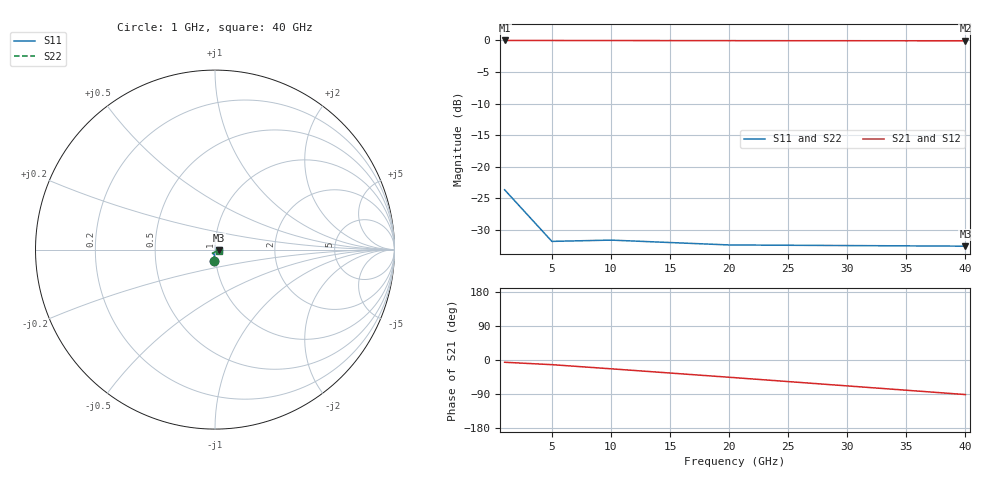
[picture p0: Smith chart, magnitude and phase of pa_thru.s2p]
! Generated by circuitRF - EM: Palace
! circuitRF-EM setup: g_thru_sheets
! circuitRF-EM layout: thru/layout/thru.clay
! circuitRF-EM written: 2026-11-04 16:05:03Z
! circuitRF-EM geometry: f9fb279984360a3e
! circuitRF-EM mesh: be36879526fbbc1a
! circuitRF-EM ports: e0915e1a10e1aaad
! circuitRF-EM model: Palace 0.18.1 (0dc74cd, schema 1-7-0)
! Port[1] = port/1
! Port[2] = port/2
! circuitRF-EM port 1: 'port/1' from 'airbox/zmin' to 'Metal1/1', wave (mode 1), 50 Ohm: Palace's S is referred to the mode's own impedance Z_PV, renormalised here to 50 Ohm; reference plane 0 um into the structure from the port face
! circuitRF-EM port 2: 'port/2' from 'airbox/zmin' to 'Metal1/1', wave (mode 1), 50 Ohm: Palace's S is referred to the mode's own impedance Z_PV, renormalised here to 50 Ohm; reference plane 0 um into the structure from the port face
! circuitRF-EM 3D mesh: 13,400 elements initially, 13,400 finally, 0 adaptive pass(es), element order 2
! circuitRF-EM 3D operating temperature: 20 C
! circuitRF-EM 3D run: preset Standard; 13400 -> 13400 tetrahedra; 93238 unknowns; 0 refinement pass(es); 5 frequency sample(s)
! circuitRF-EM 3D run cost: wall 244 s; Palace peak memory 1.4 GB
! circuitRF-EM 3D DC row: circuitRF conduction solve of the conductors, 368 elements, 0.2 s; ports as terminal pairs
! circuitRF-EM: re-running the EM setup rewrites this file. If circuitRF reports it as stale, the layout's cross-section changed after this file was written.
# GHz S RI R 50
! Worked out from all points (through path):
!   5 points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, 1 GHz to 40 GHz, reference 50 ohm
!   highest |S21| = -0.01 dB at 1 GHz (marker M1); lowest = -0.1 dB at 40 GHz (marker M2)
!   lowest |S11| = -32.6 dB at 40 GHz (marker M3), VSWR 1.05, Z = 52.4 - j0.482 ohm
!   |S11| at or under -10 dB: start of sweep to end of sweep
!   |S22| runs from -32.6 to -23.6 dB; largest |S21 - S12| = 3.6e-06
1  -0.00359 -0.0657  0.9932 -0.1039  0.9932 -0.1039  -0.00359 -0.0657
5  -0.00353 -0.0254  0.975 -0.2127  0.975 -0.2127  -0.00352 -0.0254
10  -0.00783 -0.0251  0.916 -0.3931  0.916 -0.3931  -0.00779 -0.0251
20  -0.0142 -0.0194  0.6969 -0.71  0.6969 -0.71  -0.0141 -0.0196
40  0.0231 -0.0046  -0.0203 -0.992  -0.0203 -0.992  0.023 -0.00532
